VERSION 5.7 ;
  NOWIREEXTENSIONATPIN ON ;
  DIVIDERCHAR "/" ;
  BUSBITCHARS "[]" ;
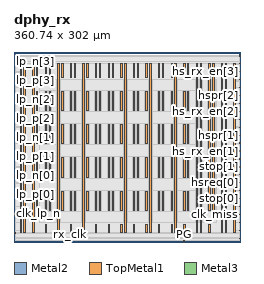
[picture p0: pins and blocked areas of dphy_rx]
MACRO dphy_rx
  CLASS BLOCK ;
  FOREIGN dphy_rx ;
  ORIGIN 0.000 0.000 ;
  SIZE 360.740 BY 302.000 ;
  PIN PG
    DIRECTION INPUT ;
    USE SIGNAL ;
    ANTENNAGATEAREA 0.180700 ;
    PORT
      LAYER Metal2 ;
        RECT 270.040 0.000 270.440 2.000 ;
    END
  END PG
  PIN VGND
    DIRECTION INOUT ;
    USE GROUND ;
    PORT
      LAYER TopMetal1 ;
        RECT 15.860 14.490 18.060 283.720 ;
    END
    PORT
      LAYER TopMetal1 ;
        RECT 35.860 49.980 38.060 80.900 ;
    END
    PORT
      LAYER TopMetal1 ;
        RECT 35.860 102.900 38.060 133.820 ;
    END
    PORT
      LAYER TopMetal1 ;
        RECT 35.860 155.820 38.060 186.740 ;
    END
    PORT
      LAYER TopMetal1 ;
        RECT 35.860 208.740 38.060 239.660 ;
    END
    PORT
      LAYER TopMetal1 ;
        RECT 35.860 261.660 38.060 283.720 ;
    END
    PORT
      LAYER TopMetal1 ;
        RECT 55.860 49.980 58.060 80.900 ;
    END
    PORT
      LAYER TopMetal1 ;
        RECT 55.860 102.900 58.060 133.820 ;
    END
    PORT
      LAYER TopMetal1 ;
        RECT 55.860 155.820 58.060 186.740 ;
    END
    PORT
      LAYER TopMetal1 ;
        RECT 55.860 208.740 58.060 239.660 ;
    END
    PORT
      LAYER TopMetal1 ;
        RECT 55.860 261.660 58.060 283.720 ;
    END
    PORT
      LAYER TopMetal1 ;
        RECT 75.860 49.980 78.060 80.900 ;
    END
    PORT
      LAYER TopMetal1 ;
        RECT 75.860 102.900 78.060 133.820 ;
    END
    PORT
      LAYER TopMetal1 ;
        RECT 75.860 155.820 78.060 186.740 ;
    END
    PORT
      LAYER TopMetal1 ;
        RECT 75.860 208.740 78.060 239.660 ;
    END
    PORT
      LAYER TopMetal1 ;
        RECT 75.860 261.660 78.060 283.720 ;
    END
    PORT
      LAYER TopMetal1 ;
        RECT 95.860 49.980 98.060 80.900 ;
    END
    PORT
      LAYER TopMetal1 ;
        RECT 95.860 102.900 98.060 133.820 ;
    END
    PORT
      LAYER TopMetal1 ;
        RECT 95.860 155.820 98.060 186.740 ;
    END
    PORT
      LAYER TopMetal1 ;
        RECT 95.860 208.740 98.060 239.660 ;
    END
    PORT
      LAYER TopMetal1 ;
        RECT 95.860 261.660 98.060 283.720 ;
    END
    PORT
      LAYER TopMetal1 ;
        RECT 115.860 49.980 118.060 80.900 ;
    END
    PORT
      LAYER TopMetal1 ;
        RECT 115.860 102.900 118.060 133.820 ;
    END
    PORT
      LAYER TopMetal1 ;
        RECT 115.860 155.820 118.060 186.740 ;
    END
    PORT
      LAYER TopMetal1 ;
        RECT 115.860 208.740 118.060 239.660 ;
    END
    PORT
      LAYER TopMetal1 ;
        RECT 115.860 261.660 118.060 283.720 ;
    END
    PORT
      LAYER TopMetal1 ;
        RECT 135.860 49.980 138.060 80.900 ;
    END
    PORT
      LAYER TopMetal1 ;
        RECT 135.860 102.900 138.060 133.820 ;
    END
    PORT
      LAYER TopMetal1 ;
        RECT 135.860 155.820 138.060 186.740 ;
    END
    PORT
      LAYER TopMetal1 ;
        RECT 135.860 208.740 138.060 239.660 ;
    END
    PORT
      LAYER TopMetal1 ;
        RECT 135.860 261.660 138.060 283.720 ;
    END
    PORT
      LAYER TopMetal1 ;
        RECT 155.860 49.980 158.060 80.900 ;
    END
    PORT
      LAYER TopMetal1 ;
        RECT 155.860 102.900 158.060 133.820 ;
    END
    PORT
      LAYER TopMetal1 ;
        RECT 155.860 155.820 158.060 186.740 ;
    END
    PORT
      LAYER TopMetal1 ;
        RECT 155.860 208.740 158.060 239.660 ;
    END
    PORT
      LAYER TopMetal1 ;
        RECT 155.860 261.660 158.060 283.720 ;
    END
    PORT
      LAYER TopMetal1 ;
        RECT 175.860 14.900 178.060 283.720 ;
    END
    PORT
      LAYER TopMetal1 ;
        RECT 195.860 49.980 198.060 80.900 ;
    END
    PORT
      LAYER TopMetal1 ;
        RECT 195.860 102.900 198.060 133.820 ;
    END
    PORT
      LAYER TopMetal1 ;
        RECT 195.860 155.820 198.060 186.740 ;
    END
    PORT
      LAYER TopMetal1 ;
        RECT 195.860 208.740 198.060 239.660 ;
    END
    PORT
      LAYER TopMetal1 ;
        RECT 195.860 261.660 198.060 283.720 ;
    END
    PORT
      LAYER TopMetal1 ;
        RECT 215.860 14.900 218.060 283.720 ;
    END
    PORT
      LAYER TopMetal1 ;
        RECT 235.860 49.980 238.060 80.900 ;
    END
    PORT
      LAYER TopMetal1 ;
        RECT 235.860 102.900 238.060 133.820 ;
    END
    PORT
      LAYER TopMetal1 ;
        RECT 235.860 155.820 238.060 186.740 ;
    END
    PORT
      LAYER TopMetal1 ;
        RECT 235.860 208.740 238.060 239.660 ;
    END
    PORT
      LAYER TopMetal1 ;
        RECT 235.860 261.660 238.060 283.720 ;
    END
    PORT
      LAYER TopMetal1 ;
        RECT 255.860 14.900 258.060 283.720 ;
    END
    PORT
      LAYER TopMetal1 ;
        RECT 275.860 49.980 278.060 80.900 ;
    END
    PORT
      LAYER TopMetal1 ;
        RECT 275.860 102.900 278.060 133.820 ;
    END
    PORT
      LAYER TopMetal1 ;
        RECT 275.860 155.820 278.060 186.740 ;
    END
    PORT
      LAYER TopMetal1 ;
        RECT 275.860 208.740 278.060 239.660 ;
    END
    PORT
      LAYER TopMetal1 ;
        RECT 275.860 261.660 278.060 283.720 ;
    END
    PORT
      LAYER TopMetal1 ;
        RECT 295.860 14.900 298.060 283.720 ;
    END
    PORT
      LAYER TopMetal1 ;
        RECT 315.860 49.980 318.060 283.720 ;
    END
    PORT
      LAYER TopMetal1 ;
        RECT 335.860 14.490 338.060 283.720 ;
    END
  END VGND
  PIN VPWR
    DIRECTION INOUT ;
    USE POWER ;
    PORT
      LAYER TopMetal1 ;
        RECT 9.660 14.900 11.860 284.130 ;
    END
    PORT
      LAYER TopMetal1 ;
        RECT 29.660 14.900 31.860 284.130 ;
    END
    PORT
      LAYER TopMetal1 ;
        RECT 49.660 14.900 51.860 27.980 ;
    END
    PORT
      LAYER TopMetal1 ;
        RECT 49.660 49.980 51.860 80.900 ;
    END
    PORT
      LAYER TopMetal1 ;
        RECT 49.660 102.900 51.860 133.820 ;
    END
    PORT
      LAYER TopMetal1 ;
        RECT 49.660 155.820 51.860 186.740 ;
    END
    PORT
      LAYER TopMetal1 ;
        RECT 49.660 208.740 51.860 239.660 ;
    END
    PORT
      LAYER TopMetal1 ;
        RECT 49.660 261.660 51.860 284.130 ;
    END
    PORT
      LAYER TopMetal1 ;
        RECT 69.660 14.900 71.860 284.130 ;
    END
    PORT
      LAYER TopMetal1 ;
        RECT 89.660 14.900 91.860 27.980 ;
    END
    PORT
      LAYER TopMetal1 ;
        RECT 89.660 49.980 91.860 80.900 ;
    END
    PORT
      LAYER TopMetal1 ;
        RECT 89.660 102.900 91.860 133.820 ;
    END
    PORT
      LAYER TopMetal1 ;
        RECT 89.660 155.820 91.860 186.740 ;
    END
    PORT
      LAYER TopMetal1 ;
        RECT 89.660 208.740 91.860 239.660 ;
    END
    PORT
      LAYER TopMetal1 ;
        RECT 89.660 261.660 91.860 284.130 ;
    END
    PORT
      LAYER TopMetal1 ;
        RECT 109.660 14.900 111.860 284.130 ;
    END
    PORT
      LAYER TopMetal1 ;
        RECT 129.660 14.900 131.860 27.980 ;
    END
    PORT
      LAYER TopMetal1 ;
        RECT 129.660 49.980 131.860 80.900 ;
    END
    PORT
      LAYER TopMetal1 ;
        RECT 129.660 102.900 131.860 133.820 ;
    END
    PORT
      LAYER TopMetal1 ;
        RECT 129.660 155.820 131.860 186.740 ;
    END
    PORT
      LAYER TopMetal1 ;
        RECT 129.660 208.740 131.860 239.660 ;
    END
    PORT
      LAYER TopMetal1 ;
        RECT 129.660 261.660 131.860 284.130 ;
    END
    PORT
      LAYER TopMetal1 ;
        RECT 149.660 14.900 151.860 27.980 ;
    END
    PORT
      LAYER TopMetal1 ;
        RECT 149.660 49.980 151.860 80.900 ;
    END
    PORT
      LAYER TopMetal1 ;
        RECT 149.660 102.900 151.860 133.820 ;
    END
    PORT
      LAYER TopMetal1 ;
        RECT 149.660 155.820 151.860 186.740 ;
    END
    PORT
      LAYER TopMetal1 ;
        RECT 149.660 208.740 151.860 239.660 ;
    END
    PORT
      LAYER TopMetal1 ;
        RECT 149.660 261.660 151.860 284.130 ;
    END
    PORT
      LAYER TopMetal1 ;
        RECT 169.660 14.900 171.860 27.980 ;
    END
    PORT
      LAYER TopMetal1 ;
        RECT 169.660 49.980 171.860 80.900 ;
    END
    PORT
      LAYER TopMetal1 ;
        RECT 169.660 102.900 171.860 133.820 ;
    END
    PORT
      LAYER TopMetal1 ;
        RECT 169.660 155.820 171.860 186.740 ;
    END
    PORT
      LAYER TopMetal1 ;
        RECT 169.660 208.740 171.860 239.660 ;
    END
    PORT
      LAYER TopMetal1 ;
        RECT 169.660 261.660 171.860 284.130 ;
    END
    PORT
      LAYER TopMetal1 ;
        RECT 189.660 14.900 191.860 27.980 ;
    END
    PORT
      LAYER TopMetal1 ;
        RECT 189.660 49.980 191.860 80.900 ;
    END
    PORT
      LAYER TopMetal1 ;
        RECT 189.660 102.900 191.860 133.820 ;
    END
    PORT
      LAYER TopMetal1 ;
        RECT 189.660 155.820 191.860 186.740 ;
    END
    PORT
      LAYER TopMetal1 ;
        RECT 189.660 208.740 191.860 239.660 ;
    END
    PORT
      LAYER TopMetal1 ;
        RECT 189.660 261.660 191.860 284.130 ;
    END
    PORT
      LAYER TopMetal1 ;
        RECT 209.660 14.900 211.860 27.980 ;
    END
    PORT
      LAYER TopMetal1 ;
        RECT 209.660 49.980 211.860 80.900 ;
    END
    PORT
      LAYER TopMetal1 ;
        RECT 209.660 102.900 211.860 133.820 ;
    END
    PORT
      LAYER TopMetal1 ;
        RECT 209.660 155.820 211.860 186.740 ;
    END
    PORT
      LAYER TopMetal1 ;
        RECT 209.660 208.740 211.860 239.660 ;
    END
    PORT
      LAYER TopMetal1 ;
        RECT 209.660 261.660 211.860 284.130 ;
    END
    PORT
      LAYER TopMetal1 ;
        RECT 229.660 14.900 231.860 27.980 ;
    END
    PORT
      LAYER TopMetal1 ;
        RECT 229.660 49.980 231.860 80.900 ;
    END
    PORT
      LAYER TopMetal1 ;
        RECT 229.660 102.900 231.860 133.820 ;
    END
    PORT
      LAYER TopMetal1 ;
        RECT 229.660 155.820 231.860 186.740 ;
    END
    PORT
      LAYER TopMetal1 ;
        RECT 229.660 208.740 231.860 239.660 ;
    END
    PORT
      LAYER TopMetal1 ;
        RECT 229.660 261.660 231.860 284.130 ;
    END
    PORT
      LAYER TopMetal1 ;
        RECT 249.660 14.900 251.860 27.980 ;
    END
    PORT
      LAYER TopMetal1 ;
        RECT 249.660 49.980 251.860 80.900 ;
    END
    PORT
      LAYER TopMetal1 ;
        RECT 249.660 102.900 251.860 133.820 ;
    END
    PORT
      LAYER TopMetal1 ;
        RECT 249.660 155.820 251.860 186.740 ;
    END
    PORT
      LAYER TopMetal1 ;
        RECT 249.660 208.740 251.860 239.660 ;
    END
    PORT
      LAYER TopMetal1 ;
        RECT 249.660 261.660 251.860 284.130 ;
    END
    PORT
      LAYER TopMetal1 ;
        RECT 269.660 14.900 271.860 27.980 ;
    END
    PORT
      LAYER TopMetal1 ;
        RECT 269.660 49.980 271.860 80.900 ;
    END
    PORT
      LAYER TopMetal1 ;
        RECT 269.660 102.900 271.860 133.820 ;
    END
    PORT
      LAYER TopMetal1 ;
        RECT 269.660 155.820 271.860 186.740 ;
    END
    PORT
      LAYER TopMetal1 ;
        RECT 269.660 208.740 271.860 239.660 ;
    END
    PORT
      LAYER TopMetal1 ;
        RECT 269.660 261.660 271.860 284.130 ;
    END
    PORT
      LAYER TopMetal1 ;
        RECT 289.660 14.900 291.860 284.130 ;
    END
    PORT
      LAYER TopMetal1 ;
        RECT 309.660 14.900 311.860 27.980 ;
    END
    PORT
      LAYER TopMetal1 ;
        RECT 309.660 49.980 311.860 284.130 ;
    END
    PORT
      LAYER TopMetal1 ;
        RECT 329.660 14.900 331.860 284.130 ;
    END
    PORT
      LAYER TopMetal1 ;
        RECT 349.660 14.900 351.860 284.130 ;
    END
  END VPWR
  PIN clk_lp_n
    DIRECTION INPUT ;
    USE SIGNAL ;
    ANTENNAGATEAREA 0.180700 ;
    PORT
      LAYER Metal3 ;
        RECT 0.000 44.420 2.000 44.820 ;
    END
  END clk_lp_n
  PIN clk_lp_p
    DIRECTION INPUT ;
    USE SIGNAL ;
    ANTENNAGATEAREA 0.180700 ;
    PORT
      LAYER Metal3 ;
        RECT 0.000 14.180 2.000 14.580 ;
    END
  END clk_lp_p
  PIN clk_miss
    DIRECTION OUTPUT ;
    USE SIGNAL ;
    ANTENNADIFFAREA 0.708600 ;
    PORT
      LAYER Metal3 ;
        RECT 358.740 43.580 360.740 43.980 ;
    END
  END clk_miss
  PIN clk_rx_en
    DIRECTION OUTPUT ;
    USE SIGNAL ;
    ANTENNADIFFAREA 0.708600 ;
    PORT
      LAYER Metal3 ;
        RECT 358.740 30.980 360.740 31.380 ;
    END
  END clk_rx_en
  PIN clk_stop
    DIRECTION OUTPUT ;
    USE SIGNAL ;
    ANTENNADIFFAREA 0.708600 ;
    PORT
      LAYER Metal3 ;
        RECT 358.740 5.780 360.740 6.180 ;
    END
  END clk_stop
  PIN clk_term_en
    DIRECTION OUTPUT ;
    USE SIGNAL ;
    ANTENNADIFFAREA 0.708600 ;
    PORT
      LAYER Metal3 ;
        RECT 358.740 18.380 360.740 18.780 ;
    END
  END clk_term_en
  PIN hs_rx_en[0]
    DIRECTION OUTPUT ;
    USE SIGNAL ;
    ANTENNADIFFAREA 0.708600 ;
    PORT
      LAYER Metal3 ;
        RECT 358.740 81.380 360.740 81.780 ;
    END
  END hs_rx_en[0]
  PIN hs_rx_en[1]
    DIRECTION OUTPUT ;
    USE SIGNAL ;
    ANTENNADIFFAREA 0.708600 ;
    PORT
      LAYER Metal3 ;
        RECT 358.740 144.380 360.740 144.780 ;
    END
  END hs_rx_en[1]
  PIN hs_rx_en[2]
    DIRECTION OUTPUT ;
    USE SIGNAL ;
    ANTENNADIFFAREA 0.708600 ;
    PORT
      LAYER Metal3 ;
        RECT 358.740 207.380 360.740 207.780 ;
    END
  END hs_rx_en[2]
  PIN hs_rx_en[3]
    DIRECTION OUTPUT ;
    USE SIGNAL ;
    ANTENNADIFFAREA 0.708600 ;
    PORT
      LAYER Metal3 ;
        RECT 358.740 270.380 360.740 270.780 ;
    END
  END hs_rx_en[3]
  PIN hspr[0]
    DIRECTION OUTPUT ;
    USE SIGNAL ;
    ANTENNADIFFAREA 0.708600 ;
    PORT
      LAYER Metal3 ;
        RECT 358.740 106.580 360.740 106.980 ;
    END
  END hspr[0]
  PIN hspr[1]
    DIRECTION OUTPUT ;
    USE SIGNAL ;
    ANTENNADIFFAREA 0.708600 ;
    PORT
      LAYER Metal3 ;
        RECT 358.740 169.580 360.740 169.980 ;
    END
  END hspr[1]
  PIN hspr[2]
    DIRECTION OUTPUT ;
    USE SIGNAL ;
    ANTENNADIFFAREA 0.708600 ;
    PORT
      LAYER Metal3 ;
        RECT 358.740 232.580 360.740 232.980 ;
    END
  END hspr[2]
  PIN hspr[3]
    DIRECTION OUTPUT ;
    USE SIGNAL ;
    ANTENNADIFFAREA 0.708600 ;
    PORT
      LAYER Metal3 ;
        RECT 358.740 295.580 360.740 295.980 ;
    END
  END hspr[3]
  PIN hsreq[0]
    DIRECTION OUTPUT ;
    USE SIGNAL ;
    ANTENNADIFFAREA 0.708600 ;
    PORT
      LAYER Metal3 ;
        RECT 358.740 93.980 360.740 94.380 ;
    END
  END hsreq[0]
  PIN hsreq[1]
    DIRECTION OUTPUT ;
    USE SIGNAL ;
    ANTENNADIFFAREA 0.708600 ;
    PORT
      LAYER Metal3 ;
        RECT 358.740 156.980 360.740 157.380 ;
    END
  END hsreq[1]
  PIN hsreq[2]
    DIRECTION OUTPUT ;
    USE SIGNAL ;
    ANTENNADIFFAREA 0.708600 ;
    PORT
      LAYER Metal3 ;
        RECT 358.740 219.980 360.740 220.380 ;
    END
  END hsreq[2]
  PIN hsreq[3]
    DIRECTION OUTPUT ;
    USE SIGNAL ;
    ANTENNADIFFAREA 0.708600 ;
    PORT
      LAYER Metal3 ;
        RECT 358.740 282.980 360.740 283.380 ;
    END
  END hsreq[3]
  PIN lp_n[0]
    DIRECTION INPUT ;
    USE SIGNAL ;
    ANTENNAGATEAREA 0.180700 ;
    PORT
      LAYER Metal3 ;
        RECT 0.000 104.900 2.000 105.300 ;
    END
  END lp_n[0]
  PIN lp_n[1]
    DIRECTION INPUT ;
    USE SIGNAL ;
    ANTENNAGATEAREA 0.180700 ;
    PORT
      LAYER Metal3 ;
        RECT 0.000 165.380 2.000 165.780 ;
    END
  END lp_n[1]
  PIN lp_n[2]
    DIRECTION INPUT ;
    USE SIGNAL ;
    ANTENNAGATEAREA 0.180700 ;
    PORT
      LAYER Metal3 ;
        RECT 0.000 225.860 2.000 226.260 ;
    END
  END lp_n[2]
  PIN lp_n[3]
    DIRECTION INPUT ;
    USE SIGNAL ;
    ANTENNAGATEAREA 0.180700 ;
    PORT
      LAYER Metal3 ;
        RECT 0.000 286.340 2.000 286.740 ;
    END
  END lp_n[3]
  PIN lp_p[0]
    DIRECTION INPUT ;
    USE SIGNAL ;
    ANTENNAGATEAREA 0.180700 ;
    PORT
      LAYER Metal3 ;
        RECT 0.000 74.660 2.000 75.060 ;
    END
  END lp_p[0]
  PIN lp_p[1]
    DIRECTION INPUT ;
    USE SIGNAL ;
    ANTENNAGATEAREA 0.180700 ;
    PORT
      LAYER Metal3 ;
        RECT 0.000 135.140 2.000 135.540 ;
    END
  END lp_p[1]
  PIN lp_p[2]
    DIRECTION INPUT ;
    USE SIGNAL ;
    ANTENNAGATEAREA 0.180700 ;
    PORT
      LAYER Metal3 ;
        RECT 0.000 195.620 2.000 196.020 ;
    END
  END lp_p[2]
  PIN lp_p[3]
    DIRECTION INPUT ;
    USE SIGNAL ;
    ANTENNAGATEAREA 0.180700 ;
    PORT
      LAYER Metal3 ;
        RECT 0.000 256.100 2.000 256.500 ;
    END
  END lp_p[3]
  PIN rx_clk
    DIRECTION INPUT ;
    USE SIGNAL ;
    ANTENNAGATEAREA 2.176200 ;
    PORT
      LAYER Metal2 ;
        RECT 89.560 0.000 89.960 2.000 ;
    END
  END rx_clk
  PIN stop[0]
    DIRECTION OUTPUT ;
    USE SIGNAL ;
    ANTENNADIFFAREA 0.708600 ;
    PORT
      LAYER Metal3 ;
        RECT 358.740 56.180 360.740 56.580 ;
    END
  END stop[0]
  PIN stop[1]
    DIRECTION OUTPUT ;
    USE SIGNAL ;
    ANTENNADIFFAREA 0.708600 ;
    PORT
      LAYER Metal3 ;
        RECT 358.740 119.180 360.740 119.580 ;
    END
  END stop[1]
  PIN stop[2]
    DIRECTION OUTPUT ;
    USE SIGNAL ;
    ANTENNADIFFAREA 0.708600 ;
    PORT
      LAYER Metal3 ;
        RECT 358.740 182.180 360.740 182.580 ;
    END
  END stop[2]
  PIN stop[3]
    DIRECTION OUTPUT ;
    USE SIGNAL ;
    ANTENNADIFFAREA 0.708600 ;
    PORT
      LAYER Metal3 ;
        RECT 358.740 245.180 360.740 245.580 ;
    END
  END stop[3]
  PIN term_en[0]
    DIRECTION OUTPUT ;
    USE SIGNAL ;
    ANTENNADIFFAREA 0.708600 ;
    PORT
      LAYER Metal3 ;
        RECT 358.740 68.780 360.740 69.180 ;
    END
  END term_en[0]
  PIN term_en[1]
    DIRECTION OUTPUT ;
    USE SIGNAL ;
    ANTENNADIFFAREA 0.708600 ;
    PORT
      LAYER Metal3 ;
        RECT 358.740 131.780 360.740 132.180 ;
    END
  END term_en[1]
  PIN term_en[2]
    DIRECTION OUTPUT ;
    USE SIGNAL ;
    ANTENNADIFFAREA 0.708600 ;
    PORT
      LAYER Metal3 ;
        RECT 358.740 194.780 360.740 195.180 ;
    END
  END term_en[2]
  PIN term_en[3]
    DIRECTION OUTPUT ;
    USE SIGNAL ;
    ANTENNADIFFAREA 0.708600 ;
    PORT
      LAYER Metal3 ;
        RECT 358.740 257.780 360.740 258.180 ;
    END
  END term_en[3]
  OBS
      LAYER GatPoly ;
        RECT 5.760 14.970 354.720 283.650 ;
      LAYER Metal1 ;
        RECT 5.760 14.900 354.720 283.720 ;
      LAYER Metal2 ;
        RECT 6.135 2.210 354.345 295.925 ;
        RECT 6.135 2.000 89.350 2.210 ;
        RECT 90.170 2.000 269.830 2.210 ;
        RECT 270.650 2.000 354.345 2.210 ;
      LAYER Metal3 ;
        RECT 2.000 295.370 358.530 295.880 ;
        RECT 2.000 286.950 358.740 295.370 ;
        RECT 2.210 286.130 358.740 286.950 ;
        RECT 2.000 283.590 358.740 286.130 ;
        RECT 2.000 282.770 358.530 283.590 ;
        RECT 2.000 270.990 358.740 282.770 ;
        RECT 2.000 270.170 358.530 270.990 ;
        RECT 2.000 258.390 358.740 270.170 ;
        RECT 2.000 257.570 358.530 258.390 ;
        RECT 2.000 256.710 358.740 257.570 ;
        RECT 2.210 255.890 358.740 256.710 ;
        RECT 2.000 245.790 358.740 255.890 ;
        RECT 2.000 244.970 358.530 245.790 ;
        RECT 2.000 233.190 358.740 244.970 ;
        RECT 2.000 232.370 358.530 233.190 ;
        RECT 2.000 226.470 358.740 232.370 ;
        RECT 2.210 225.650 358.740 226.470 ;
        RECT 2.000 220.590 358.740 225.650 ;
        RECT 2.000 219.770 358.530 220.590 ;
        RECT 2.000 207.990 358.740 219.770 ;
        RECT 2.000 207.170 358.530 207.990 ;
        RECT 2.000 196.230 358.740 207.170 ;
        RECT 2.210 195.410 358.740 196.230 ;
        RECT 2.000 195.390 358.740 195.410 ;
        RECT 2.000 194.570 358.530 195.390 ;
        RECT 2.000 182.790 358.740 194.570 ;
        RECT 2.000 181.970 358.530 182.790 ;
        RECT 2.000 170.190 358.740 181.970 ;
        RECT 2.000 169.370 358.530 170.190 ;
        RECT 2.000 165.990 358.740 169.370 ;
        RECT 2.210 165.170 358.740 165.990 ;
        RECT 2.000 157.590 358.740 165.170 ;
        RECT 2.000 156.770 358.530 157.590 ;
        RECT 2.000 144.990 358.740 156.770 ;
        RECT 2.000 144.170 358.530 144.990 ;
        RECT 2.000 135.750 358.740 144.170 ;
        RECT 2.210 134.930 358.740 135.750 ;
        RECT 2.000 132.390 358.740 134.930 ;
        RECT 2.000 131.570 358.530 132.390 ;
        RECT 2.000 119.790 358.740 131.570 ;
        RECT 2.000 118.970 358.530 119.790 ;
        RECT 2.000 107.190 358.740 118.970 ;
        RECT 2.000 106.370 358.530 107.190 ;
        RECT 2.000 105.510 358.740 106.370 ;
        RECT 2.210 104.690 358.740 105.510 ;
        RECT 2.000 94.590 358.740 104.690 ;
        RECT 2.000 93.770 358.530 94.590 ;
        RECT 2.000 81.990 358.740 93.770 ;
        RECT 2.000 81.170 358.530 81.990 ;
        RECT 2.000 75.270 358.740 81.170 ;
        RECT 2.210 74.450 358.740 75.270 ;
        RECT 2.000 69.390 358.740 74.450 ;
        RECT 2.000 68.570 358.530 69.390 ;
        RECT 2.000 56.790 358.740 68.570 ;
        RECT 2.000 55.970 358.530 56.790 ;
        RECT 2.000 45.030 358.740 55.970 ;
        RECT 2.210 44.210 358.740 45.030 ;
        RECT 2.000 44.190 358.740 44.210 ;
        RECT 2.000 43.370 358.530 44.190 ;
        RECT 2.000 31.590 358.740 43.370 ;
        RECT 2.000 30.770 358.530 31.590 ;
        RECT 2.000 18.990 358.740 30.770 ;
        RECT 2.000 18.170 358.530 18.990 ;
        RECT 2.000 14.790 358.740 18.170 ;
        RECT 2.210 13.970 358.740 14.790 ;
        RECT 2.000 6.390 358.740 13.970 ;
        RECT 2.000 5.570 358.530 6.390 ;
        RECT 2.000 2.520 358.740 5.570 ;
      LAYER Metal4 ;
        RECT 9.840 14.975 351.680 283.645 ;
      LAYER Metal5 ;
        RECT 9.660 14.810 351.860 283.810 ;
      LAYER TopMetal1 ;
        RECT 41.270 241.300 68.020 258.380 ;
        RECT 41.270 207.100 48.020 241.300 ;
        RECT 53.500 207.100 54.220 241.300 ;
        RECT 59.700 207.100 68.020 241.300 ;
        RECT 41.270 188.380 68.020 207.100 ;
        RECT 41.270 154.180 48.020 188.380 ;
        RECT 53.500 154.180 54.220 188.380 ;
        RECT 59.700 154.180 68.020 188.380 ;
        RECT 41.270 135.460 68.020 154.180 ;
        RECT 41.270 101.260 48.020 135.460 ;
        RECT 53.500 101.260 54.220 135.460 ;
        RECT 59.700 101.260 68.020 135.460 ;
        RECT 41.270 82.540 68.020 101.260 ;
        RECT 41.270 48.340 48.020 82.540 ;
        RECT 53.500 48.340 54.220 82.540 ;
        RECT 59.700 48.340 68.020 82.540 ;
        RECT 41.270 31.260 68.020 48.340 ;
        RECT 73.500 241.300 108.020 258.380 ;
        RECT 73.500 207.100 74.220 241.300 ;
        RECT 79.700 207.100 88.020 241.300 ;
        RECT 93.500 207.100 94.220 241.300 ;
        RECT 99.700 207.100 108.020 241.300 ;
        RECT 73.500 188.380 108.020 207.100 ;
        RECT 73.500 154.180 74.220 188.380 ;
        RECT 79.700 154.180 88.020 188.380 ;
        RECT 93.500 154.180 94.220 188.380 ;
        RECT 99.700 154.180 108.020 188.380 ;
        RECT 73.500 135.460 108.020 154.180 ;
        RECT 73.500 101.260 74.220 135.460 ;
        RECT 79.700 101.260 88.020 135.460 ;
        RECT 93.500 101.260 94.220 135.460 ;
        RECT 99.700 101.260 108.020 135.460 ;
        RECT 73.500 82.540 108.020 101.260 ;
        RECT 73.500 48.340 74.220 82.540 ;
        RECT 79.700 48.340 88.020 82.540 ;
        RECT 93.500 48.340 94.220 82.540 ;
        RECT 99.700 48.340 108.020 82.540 ;
        RECT 73.500 31.260 108.020 48.340 ;
        RECT 113.500 241.300 174.220 258.380 ;
        RECT 113.500 207.100 114.220 241.300 ;
        RECT 119.700 207.100 128.020 241.300 ;
        RECT 133.500 207.100 134.220 241.300 ;
        RECT 139.700 207.100 148.020 241.300 ;
        RECT 153.500 207.100 154.220 241.300 ;
        RECT 159.700 207.100 168.020 241.300 ;
        RECT 173.500 207.100 174.220 241.300 ;
        RECT 113.500 188.380 174.220 207.100 ;
        RECT 113.500 154.180 114.220 188.380 ;
        RECT 119.700 154.180 128.020 188.380 ;
        RECT 133.500 154.180 134.220 188.380 ;
        RECT 139.700 154.180 148.020 188.380 ;
        RECT 153.500 154.180 154.220 188.380 ;
        RECT 159.700 154.180 168.020 188.380 ;
        RECT 173.500 154.180 174.220 188.380 ;
        RECT 113.500 135.460 174.220 154.180 ;
        RECT 113.500 101.260 114.220 135.460 ;
        RECT 119.700 101.260 128.020 135.460 ;
        RECT 133.500 101.260 134.220 135.460 ;
        RECT 139.700 101.260 148.020 135.460 ;
        RECT 153.500 101.260 154.220 135.460 ;
        RECT 159.700 101.260 168.020 135.460 ;
        RECT 173.500 101.260 174.220 135.460 ;
        RECT 113.500 82.540 174.220 101.260 ;
        RECT 113.500 48.340 114.220 82.540 ;
        RECT 119.700 48.340 128.020 82.540 ;
        RECT 133.500 48.340 134.220 82.540 ;
        RECT 139.700 48.340 148.020 82.540 ;
        RECT 153.500 48.340 154.220 82.540 ;
        RECT 159.700 48.340 168.020 82.540 ;
        RECT 173.500 48.340 174.220 82.540 ;
        RECT 113.500 31.260 174.220 48.340 ;
        RECT 179.700 241.300 214.220 258.380 ;
        RECT 179.700 207.100 188.020 241.300 ;
        RECT 193.500 207.100 194.220 241.300 ;
        RECT 199.700 207.100 208.020 241.300 ;
        RECT 213.500 207.100 214.220 241.300 ;
        RECT 179.700 188.380 214.220 207.100 ;
        RECT 179.700 154.180 188.020 188.380 ;
        RECT 193.500 154.180 194.220 188.380 ;
        RECT 199.700 154.180 208.020 188.380 ;
        RECT 213.500 154.180 214.220 188.380 ;
        RECT 179.700 135.460 214.220 154.180 ;
        RECT 179.700 101.260 188.020 135.460 ;
        RECT 193.500 101.260 194.220 135.460 ;
        RECT 199.700 101.260 208.020 135.460 ;
        RECT 213.500 101.260 214.220 135.460 ;
        RECT 179.700 82.540 214.220 101.260 ;
        RECT 179.700 48.340 188.020 82.540 ;
        RECT 193.500 48.340 194.220 82.540 ;
        RECT 199.700 48.340 208.020 82.540 ;
        RECT 213.500 48.340 214.220 82.540 ;
        RECT 179.700 31.260 214.220 48.340 ;
        RECT 219.700 241.300 254.220 258.380 ;
        RECT 219.700 207.100 228.020 241.300 ;
        RECT 233.500 207.100 234.220 241.300 ;
        RECT 239.700 207.100 248.020 241.300 ;
        RECT 253.500 207.100 254.220 241.300 ;
        RECT 219.700 188.380 254.220 207.100 ;
        RECT 219.700 154.180 228.020 188.380 ;
        RECT 233.500 154.180 234.220 188.380 ;
        RECT 239.700 154.180 248.020 188.380 ;
        RECT 253.500 154.180 254.220 188.380 ;
        RECT 219.700 135.460 254.220 154.180 ;
        RECT 219.700 101.260 228.020 135.460 ;
        RECT 233.500 101.260 234.220 135.460 ;
        RECT 239.700 101.260 248.020 135.460 ;
        RECT 253.500 101.260 254.220 135.460 ;
        RECT 219.700 82.540 254.220 101.260 ;
        RECT 219.700 48.340 228.020 82.540 ;
        RECT 233.500 48.340 234.220 82.540 ;
        RECT 239.700 48.340 248.020 82.540 ;
        RECT 253.500 48.340 254.220 82.540 ;
        RECT 219.700 31.260 254.220 48.340 ;
        RECT 259.700 241.300 288.020 258.380 ;
        RECT 259.700 207.100 268.020 241.300 ;
        RECT 273.500 207.100 274.220 241.300 ;
        RECT 279.700 207.100 288.020 241.300 ;
        RECT 259.700 188.380 288.020 207.100 ;
        RECT 259.700 154.180 268.020 188.380 ;
        RECT 273.500 154.180 274.220 188.380 ;
        RECT 279.700 154.180 288.020 188.380 ;
        RECT 259.700 135.460 288.020 154.180 ;
        RECT 259.700 101.260 268.020 135.460 ;
        RECT 273.500 101.260 274.220 135.460 ;
        RECT 279.700 101.260 288.020 135.460 ;
        RECT 259.700 82.540 288.020 101.260 ;
        RECT 259.700 48.340 268.020 82.540 ;
        RECT 273.500 48.340 274.220 82.540 ;
        RECT 279.700 48.340 288.020 82.540 ;
        RECT 259.700 31.260 288.020 48.340 ;
        RECT 293.500 31.260 294.220 258.380 ;
        RECT 299.700 48.340 308.020 258.380 ;
        RECT 313.500 48.340 314.220 258.380 ;
        RECT 319.700 48.340 321.750 258.380 ;
        RECT 299.700 31.260 321.750 48.340 ;
  END
END dphy_rx
END LIBRARY

